VERSION 5.7 ;
  NOWIREEXTENSIONATPIN ON ;
  DIVIDERCHAR "/" ;
  BUSBITCHARS "[]" ;
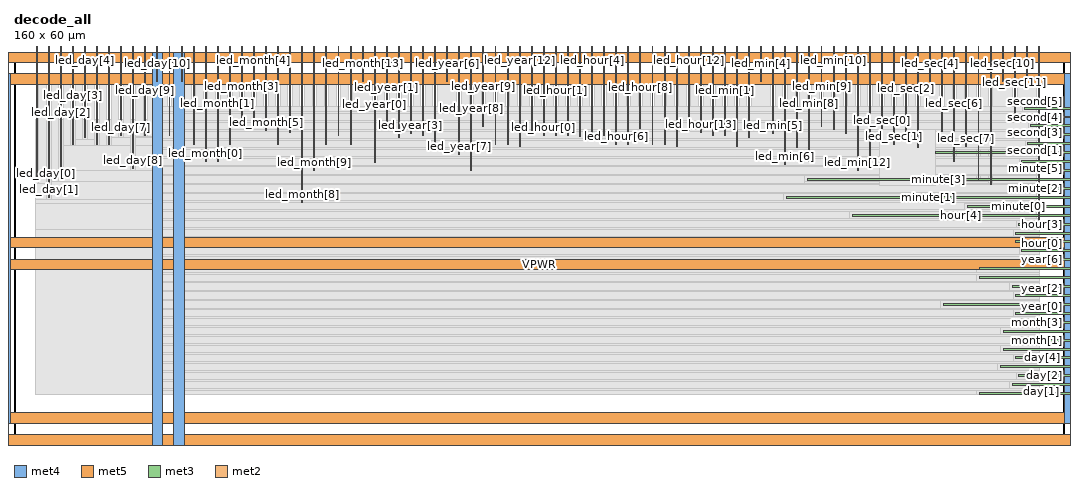
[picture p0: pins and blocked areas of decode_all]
MACRO decode_all
  CLASS BLOCK ;
  FOREIGN decode_all ;
  ORIGIN 0.000 0.000 ;
  SIZE 160.000 BY 60.000 ;
  PIN VGND
    DIRECTION INOUT ;
    USE GROUND ;
    PORT
      LAYER met4 ;
        RECT -5.380 -0.020 -3.780 59.860 ;
    END
    PORT
      LAYER met5 ;
        RECT -5.380 -0.020 165.000 1.580 ;
    END
    PORT
      LAYER met5 ;
        RECT -5.380 58.260 165.000 59.860 ;
    END
    PORT
      LAYER met4 ;
        RECT 163.400 -0.020 165.000 59.860 ;
    END
    PORT
      LAYER met4 ;
        RECT 24.340 -0.020 25.940 59.860 ;
    END
    PORT
      LAYER met5 ;
        RECT -5.380 30.030 165.000 31.630 ;
    END
  END VGND
  PIN VPWR
    DIRECTION INOUT ;
    USE POWER ;
    PORT
      LAYER met4 ;
        RECT -2.080 3.280 -0.480 56.560 ;
    END
    PORT
      LAYER met5 ;
        RECT -2.080 3.280 161.700 4.880 ;
    END
    PORT
      LAYER met5 ;
        RECT -2.080 54.960 161.700 56.560 ;
    END
    PORT
      LAYER met4 ;
        RECT 160.100 3.280 161.700 56.560 ;
    END
    PORT
      LAYER met4 ;
        RECT 21.040 -0.020 22.640 59.860 ;
    END
    PORT
      LAYER met5 ;
        RECT -5.380 26.730 165.000 28.330 ;
    END
  END VPWR
  PIN day[0]
    DIRECTION INPUT ;
    USE SIGNAL ;
    ANTENNAGATEAREA 0.159000 ;
    PORT
      LAYER met3 ;
        RECT 147.110 7.670 161.000 7.970 ;
    END
  END day[0]
  PIN day[1]
    DIRECTION INPUT ;
    USE SIGNAL ;
    ANTENNAGATEAREA 0.213000 ;
    PORT
      LAYER met3 ;
        RECT 152.170 9.030 161.000 9.330 ;
    END
  END day[1]
  PIN day[2]
    DIRECTION INPUT ;
    USE SIGNAL ;
    ANTENNAGATEAREA 0.213000 ;
    PORT
      LAYER met3 ;
        RECT 153.090 10.390 161.000 10.690 ;
    END
  END day[2]
  PIN day[3]
    DIRECTION INPUT ;
    USE SIGNAL ;
    ANTENNAGATEAREA 0.213000 ;
    PORT
      LAYER met3 ;
        RECT 150.330 11.750 161.000 12.050 ;
    END
  END day[3]
  PIN day[4]
    DIRECTION INPUT ;
    USE SIGNAL ;
    ANTENNAGATEAREA 0.159000 ;
    PORT
      LAYER met3 ;
        RECT 152.630 13.110 161.000 13.410 ;
    END
  END day[4]
  PIN hour[0]
    DIRECTION INPUT ;
    USE SIGNAL ;
    ANTENNAGATEAREA 0.213000 ;
    PORT
      LAYER met3 ;
        RECT 153.550 29.430 161.000 29.730 ;
    END
  END hour[0]
  PIN hour[1]
    DIRECTION INPUT ;
    USE SIGNAL ;
    ANTENNAGATEAREA 0.126000 ;
    PORT
      LAYER met3 ;
        RECT 152.630 30.790 161.000 31.090 ;
    END
  END hour[1]
  PIN hour[2]
    DIRECTION INPUT ;
    USE SIGNAL ;
    ANTENNAGATEAREA 0.126000 ;
    PORT
      LAYER met3 ;
        RECT 152.630 32.150 161.000 32.450 ;
    END
  END hour[2]
  PIN hour[3]
    DIRECTION INPUT ;
    USE SIGNAL ;
    ANTENNAGATEAREA 0.196500 ;
    PORT
      LAYER met3 ;
        RECT 153.090 33.510 161.000 33.810 ;
    END
  END hour[3]
  PIN hour[4]
    DIRECTION INPUT ;
    USE SIGNAL ;
    ANTENNAGATEAREA 0.213000 ;
    PORT
      LAYER met3 ;
        RECT 127.790 34.870 161.000 35.170 ;
    END
  END hour[4]
  PIN led_day[0]
    DIRECTION OUTPUT ;
    USE SIGNAL ;
    ANTENNADIFFAREA 0.445500 ;
    PORT
      LAYER met2 ;
        RECT 3.380 40.080 3.520 61.000 ;
    END
  END led_day[0]
  PIN led_day[10]
    DIRECTION OUTPUT ;
    USE SIGNAL ;
    ANTENNADIFFAREA 0.445500 ;
    PORT
      LAYER met2 ;
        RECT 21.780 55.350 21.920 61.000 ;
    END
  END led_day[10]
  PIN led_day[11]
    DIRECTION OUTPUT ;
    USE SIGNAL ;
    ANTENNADIFFAREA 0.445500 ;
    PORT
      LAYER met2 ;
        RECT 23.620 47.190 23.760 61.000 ;
    END
  END led_day[11]
  PIN led_day[12]
    DIRECTION OUTPUT ;
    USE SIGNAL ;
    ANTENNADIFFAREA 0.445500 ;
    PORT
      LAYER met2 ;
        RECT 25.460 55.350 25.600 61.000 ;
    END
  END led_day[12]
  PIN led_day[13]
    DIRECTION OUTPUT ;
    USE SIGNAL ;
    ANTENNADIFFAREA 0.445500 ;
    PORT
      LAYER met2 ;
        RECT 27.300 45.860 27.440 61.000 ;
    END
  END led_day[13]
  PIN led_day[1]
    DIRECTION OUTPUT ;
    USE SIGNAL ;
    ANTENNADIFFAREA 0.445500 ;
    PORT
      LAYER met2 ;
        RECT 5.220 37.700 5.360 61.000 ;
    END
  END led_day[1]
  PIN led_day[2]
    DIRECTION OUTPUT ;
    USE SIGNAL ;
    ANTENNADIFFAREA 0.445500 ;
    PORT
      LAYER met2 ;
        RECT 7.060 40.420 7.200 61.000 ;
    END
  END led_day[2]
  PIN led_day[3]
    DIRECTION OUTPUT ;
    USE SIGNAL ;
    ANTENNADIFFAREA 0.445500 ;
    PORT
      LAYER met2 ;
        RECT 8.900 45.860 9.040 61.000 ;
    END
  END led_day[3]
  PIN led_day[4]
    DIRECTION OUTPUT ;
    USE SIGNAL ;
    ANTENNADIFFAREA 0.445500 ;
    PORT
      LAYER met2 ;
        RECT 10.740 46.880 10.880 61.000 ;
    END
  END led_day[4]
  PIN led_day[5]
    DIRECTION OUTPUT ;
    USE SIGNAL ;
    ANTENNADIFFAREA 0.445500 ;
    PORT
      LAYER met2 ;
        RECT 12.580 45.860 12.720 61.000 ;
    END
  END led_day[5]
  PIN led_day[6]
    DIRECTION OUTPUT ;
    USE SIGNAL ;
    ANTENNADIFFAREA 0.445500 ;
    PORT
      LAYER met2 ;
        RECT 14.420 45.860 14.560 61.000 ;
    END
  END led_day[6]
  PIN led_day[7]
    DIRECTION OUTPUT ;
    USE SIGNAL ;
    ANTENNADIFFAREA 0.445500 ;
    PORT
      LAYER met2 ;
        RECT 16.260 47.190 16.400 61.000 ;
    END
  END led_day[7]
  PIN led_day[8]
    DIRECTION OUTPUT ;
    USE SIGNAL ;
    PORT
      LAYER met2 ;
        RECT 18.100 42.120 18.240 61.000 ;
    END
  END led_day[8]
  PIN led_day[9]
    DIRECTION OUTPUT ;
    USE SIGNAL ;
    ANTENNADIFFAREA 0.445500 ;
    PORT
      LAYER met2 ;
        RECT 19.940 47.220 20.080 61.000 ;
    END
  END led_day[9]
  PIN led_hour[0]
    DIRECTION OUTPUT ;
    USE SIGNAL ;
    ANTENNADIFFAREA 0.445500 ;
    PORT
      LAYER met2 ;
        RECT 80.660 47.220 80.800 61.000 ;
    END
  END led_hour[0]
  PIN led_hour[10]
    DIRECTION OUTPUT ;
    USE SIGNAL ;
    ANTENNADIFFAREA 0.445500 ;
    PORT
      LAYER met2 ;
        RECT 99.060 45.860 99.200 61.000 ;
    END
  END led_hour[10]
  PIN led_hour[11]
    DIRECTION OUTPUT ;
    USE SIGNAL ;
    ANTENNADIFFAREA 0.445500 ;
    PORT
      LAYER met2 ;
        RECT 100.900 45.520 101.040 61.000 ;
    END
  END led_hour[11]
  PIN led_hour[12]
    DIRECTION OUTPUT ;
    USE SIGNAL ;
    ANTENNADIFFAREA 0.445500 ;
    PORT
      LAYER met2 ;
        RECT 102.740 47.870 102.880 61.000 ;
    END
  END led_hour[12]
  PIN led_hour[13]
    DIRECTION OUTPUT ;
    USE SIGNAL ;
    ANTENNADIFFAREA 0.445500 ;
    PORT
      LAYER met2 ;
        RECT 104.580 47.560 104.720 61.000 ;
    END
  END led_hour[13]
  PIN led_hour[1]
    DIRECTION OUTPUT ;
    USE SIGNAL ;
    ANTENNADIFFAREA 0.445500 ;
    PORT
      LAYER met2 ;
        RECT 82.500 47.220 82.640 61.000 ;
    END
  END led_hour[1]
  PIN led_hour[2]
    DIRECTION OUTPUT ;
    USE SIGNAL ;
    ANTENNADIFFAREA 0.445500 ;
    PORT
      LAYER met2 ;
        RECT 84.340 47.220 84.480 61.000 ;
    END
  END led_hour[2]
  PIN led_hour[3]
    DIRECTION OUTPUT ;
    USE SIGNAL ;
    ANTENNADIFFAREA 0.445500 ;
    PORT
      LAYER met2 ;
        RECT 86.180 47.020 86.320 61.000 ;
    END
  END led_hour[3]
  PIN led_hour[4]
    DIRECTION OUTPUT ;
    USE SIGNAL ;
    ANTENNADIFFAREA 0.445500 ;
    PORT
      LAYER met2 ;
        RECT 88.020 47.560 88.160 61.000 ;
    END
  END led_hour[4]
  PIN led_hour[5]
    DIRECTION OUTPUT ;
    USE SIGNAL ;
    ANTENNADIFFAREA 0.445500 ;
    PORT
      LAYER met2 ;
        RECT 89.860 47.220 90.000 61.000 ;
    END
  END led_hour[5]
  PIN led_hour[6]
    DIRECTION OUTPUT ;
    USE SIGNAL ;
    ANTENNADIFFAREA 0.445500 ;
    PORT
      LAYER met2 ;
        RECT 91.700 45.860 91.840 61.000 ;
    END
  END led_hour[6]
  PIN led_hour[7]
    DIRECTION OUTPUT ;
    USE SIGNAL ;
    ANTENNADIFFAREA 0.445500 ;
    PORT
      LAYER met2 ;
        RECT 93.540 45.860 93.680 61.000 ;
    END
  END led_hour[7]
  PIN led_hour[8]
    DIRECTION OUTPUT ;
    USE SIGNAL ;
    PORT
      LAYER met2 ;
        RECT 95.380 48.240 95.520 61.000 ;
    END
  END led_hour[8]
  PIN led_hour[9]
    DIRECTION OUTPUT ;
    USE SIGNAL ;
    ANTENNADIFFAREA 0.445500 ;
    PORT
      LAYER met2 ;
        RECT 97.220 45.860 97.360 61.000 ;
    END
  END led_hour[9]
  PIN led_min[0]
    DIRECTION OUTPUT ;
    USE SIGNAL ;
    ANTENNADIFFAREA 0.445500 ;
    PORT
      LAYER met2 ;
        RECT 106.420 47.190 106.560 61.000 ;
    END
  END led_min[0]
  PIN led_min[10]
    DIRECTION OUTPUT ;
    USE SIGNAL ;
    ANTENNADIFFAREA 0.445500 ;
    PORT
      LAYER met2 ;
        RECT 124.820 48.080 124.960 61.000 ;
    END
  END led_min[10]
  PIN led_min[11]
    DIRECTION OUTPUT ;
    USE SIGNAL ;
    ANTENNADIFFAREA 0.445500 ;
    PORT
      LAYER met2 ;
        RECT 126.660 47.400 126.800 61.000 ;
    END
  END led_min[11]
  PIN led_min[12]
    DIRECTION OUTPUT ;
    USE SIGNAL ;
    ANTENNADIFFAREA 0.445500 ;
    PORT
      LAYER met2 ;
        RECT 128.500 41.780 128.640 61.000 ;
    END
  END led_min[12]
  PIN led_min[13]
    DIRECTION OUTPUT ;
    USE SIGNAL ;
    ANTENNADIFFAREA 0.445500 ;
    PORT
      LAYER met2 ;
        RECT 130.340 44.000 130.480 61.000 ;
    END
  END led_min[13]
  PIN led_min[1]
    DIRECTION OUTPUT ;
    USE SIGNAL ;
    ANTENNADIFFAREA 0.445500 ;
    PORT
      LAYER met2 ;
        RECT 108.260 47.220 108.400 61.000 ;
    END
  END led_min[1]
  PIN led_min[2]
    DIRECTION OUTPUT ;
    USE SIGNAL ;
    ANTENNADIFFAREA 0.445500 ;
    PORT
      LAYER met2 ;
        RECT 110.100 45.520 110.240 61.000 ;
    END
  END led_min[2]
  PIN led_min[3]
    DIRECTION OUTPUT ;
    USE SIGNAL ;
    ANTENNADIFFAREA 0.445500 ;
    PORT
      LAYER met2 ;
        RECT 111.940 46.880 112.080 61.000 ;
    END
  END led_min[3]
  PIN led_min[4]
    DIRECTION OUTPUT ;
    USE SIGNAL ;
    ANTENNADIFFAREA 0.445500 ;
    PORT
      LAYER met2 ;
        RECT 113.780 55.350 113.920 61.000 ;
    END
  END led_min[4]
  PIN led_min[5]
    DIRECTION OUTPUT ;
    USE SIGNAL ;
    ANTENNADIFFAREA 0.445500 ;
    PORT
      LAYER met2 ;
        RECT 115.620 47.400 115.760 61.000 ;
    END
  END led_min[5]
  PIN led_min[6]
    DIRECTION OUTPUT ;
    USE SIGNAL ;
    ANTENNADIFFAREA 0.445500 ;
    PORT
      LAYER met2 ;
        RECT 117.460 42.800 117.600 61.000 ;
    END
  END led_min[6]
  PIN led_min[7]
    DIRECTION OUTPUT ;
    USE SIGNAL ;
    ANTENNADIFFAREA 0.445500 ;
    PORT
      LAYER met2 ;
        RECT 119.300 45.360 119.440 61.000 ;
    END
  END led_min[7]
  PIN led_min[8]
    DIRECTION OUTPUT ;
    USE SIGNAL ;
    ANTENNADIFFAREA 0.445500 ;
    PORT
      LAYER met2 ;
        RECT 121.140 43.140 121.280 61.000 ;
    END
  END led_min[8]
  PIN led_min[9]
    DIRECTION OUTPUT ;
    USE SIGNAL ;
    ANTENNADIFFAREA 0.445500 ;
    PORT
      LAYER met2 ;
        RECT 122.980 48.550 123.120 61.000 ;
    END
  END led_min[9]
  PIN led_month[0]
    DIRECTION OUTPUT ;
    USE SIGNAL ;
    ANTENNADIFFAREA 0.445500 ;
    PORT
      LAYER met2 ;
        RECT 29.140 43.140 29.280 61.000 ;
    END
  END led_month[0]
  PIN led_month[10]
    DIRECTION OUTPUT ;
    USE SIGNAL ;
    ANTENNADIFFAREA 0.445500 ;
    PORT
      LAYER met2 ;
        RECT 47.540 45.860 47.680 61.000 ;
    END
  END led_month[10]
  PIN led_month[11]
    DIRECTION OUTPUT ;
    USE SIGNAL ;
    ANTENNADIFFAREA 0.445500 ;
    PORT
      LAYER met2 ;
        RECT 49.380 47.220 49.520 61.000 ;
    END
  END led_month[11]
  PIN led_month[12]
    DIRECTION OUTPUT ;
    USE SIGNAL ;
    ANTENNADIFFAREA 0.445500 ;
    PORT
      LAYER met2 ;
        RECT 51.220 45.860 51.360 61.000 ;
    END
  END led_month[12]
  PIN led_month[13]
    DIRECTION OUTPUT ;
    USE SIGNAL ;
    PORT
      LAYER met2 ;
        RECT 53.060 55.350 53.200 61.000 ;
    END
  END led_month[13]
  PIN led_month[1]
    DIRECTION OUTPUT ;
    USE SIGNAL ;
    ANTENNADIFFAREA 0.445500 ;
    PORT
      LAYER met2 ;
        RECT 30.980 43.140 31.120 61.000 ;
    END
  END led_month[1]
  PIN led_month[2]
    DIRECTION OUTPUT ;
    USE SIGNAL ;
    ANTENNADIFFAREA 0.445500 ;
    PORT
      LAYER met2 ;
        RECT 32.820 45.860 32.960 61.000 ;
    END
  END led_month[2]
  PIN led_month[3]
    DIRECTION OUTPUT ;
    USE SIGNAL ;
    ANTENNADIFFAREA 0.445500 ;
    PORT
      LAYER met2 ;
        RECT 34.660 48.550 34.800 61.000 ;
    END
  END led_month[3]
  PIN led_month[4]
    DIRECTION OUTPUT ;
    USE SIGNAL ;
    ANTENNADIFFAREA 0.445500 ;
    PORT
      LAYER met2 ;
        RECT 36.500 48.550 36.640 61.000 ;
    END
  END led_month[4]
  PIN led_month[5]
    DIRECTION OUTPUT ;
    USE SIGNAL ;
    ANTENNADIFFAREA 0.445500 ;
    PORT
      LAYER met2 ;
        RECT 38.340 47.870 38.480 61.000 ;
    END
  END led_month[5]
  PIN led_month[6]
    DIRECTION OUTPUT ;
    USE SIGNAL ;
    ANTENNADIFFAREA 0.445500 ;
    PORT
      LAYER met2 ;
        RECT 40.180 45.860 40.320 61.000 ;
    END
  END led_month[6]
  PIN led_month[7]
    DIRECTION OUTPUT ;
    USE SIGNAL ;
    ANTENNADIFFAREA 0.445500 ;
    PORT
      LAYER met2 ;
        RECT 42.020 47.560 42.160 61.000 ;
    END
  END led_month[7]
  PIN led_month[8]
    DIRECTION OUTPUT ;
    USE SIGNAL ;
    PORT
      LAYER met2 ;
        RECT 43.860 37.020 44.000 61.000 ;
    END
  END led_month[8]
  PIN led_month[9]
    DIRECTION OUTPUT ;
    USE SIGNAL ;
    PORT
      LAYER met2 ;
        RECT 45.700 41.780 45.840 61.000 ;
    END
  END led_month[9]
  PIN led_sec[0]
    DIRECTION OUTPUT ;
    USE SIGNAL ;
    ANTENNADIFFAREA 0.445500 ;
    PORT
      LAYER met2 ;
        RECT 132.180 48.230 132.320 61.000 ;
    END
  END led_sec[0]
  PIN led_sec[10]
    DIRECTION OUTPUT ;
    USE SIGNAL ;
    ANTENNADIFFAREA 0.445500 ;
    PORT
      LAYER met2 ;
        RECT 150.580 55.350 150.720 61.000 ;
    END
  END led_sec[10]
  PIN led_sec[11]
    DIRECTION OUTPUT ;
    USE SIGNAL ;
    ANTENNADIFFAREA 0.445500 ;
    PORT
      LAYER met2 ;
        RECT 152.420 49.600 152.560 61.000 ;
    END
  END led_sec[11]
  PIN led_sec[12]
    DIRECTION OUTPUT ;
    USE SIGNAL ;
    ANTENNADIFFAREA 0.445500 ;
    PORT
      LAYER met2 ;
        RECT 154.260 55.350 154.400 61.000 ;
    END
  END led_sec[12]
  PIN led_sec[13]
    DIRECTION OUTPUT ;
    USE SIGNAL ;
    ANTENNADIFFAREA 0.445500 ;
    PORT
      LAYER met2 ;
        RECT 156.100 33.120 156.240 61.000 ;
    END
  END led_sec[13]
  PIN led_sec[1]
    DIRECTION OUTPUT ;
    USE SIGNAL ;
    ANTENNADIFFAREA 0.445500 ;
    PORT
      LAYER met2 ;
        RECT 134.020 45.860 134.160 61.000 ;
    END
  END led_sec[1]
  PIN led_sec[2]
    DIRECTION OUTPUT ;
    USE SIGNAL ;
    ANTENNADIFFAREA 0.445500 ;
    PORT
      LAYER met2 ;
        RECT 135.860 47.700 136.000 61.000 ;
    END
  END led_sec[2]
  PIN led_sec[3]
    DIRECTION OUTPUT ;
    USE SIGNAL ;
    ANTENNADIFFAREA 0.445500 ;
    PORT
      LAYER met2 ;
        RECT 137.700 45.320 137.840 61.000 ;
    END
  END led_sec[3]
  PIN led_sec[4]
    DIRECTION OUTPUT ;
    USE SIGNAL ;
    ANTENNADIFFAREA 0.445500 ;
    PORT
      LAYER met2 ;
        RECT 139.540 55.350 139.680 61.000 ;
    END
  END led_sec[4]
  PIN led_sec[5]
    DIRECTION OUTPUT ;
    USE SIGNAL ;
    ANTENNADIFFAREA 0.445500 ;
    PORT
      LAYER met2 ;
        RECT 141.380 47.700 141.520 61.000 ;
    END
  END led_sec[5]
  PIN led_sec[6]
    DIRECTION OUTPUT ;
    USE SIGNAL ;
    ANTENNADIFFAREA 0.445500 ;
    PORT
      LAYER met2 ;
        RECT 143.220 43.140 143.360 61.000 ;
    END
  END led_sec[6]
  PIN led_sec[7]
    DIRECTION OUTPUT ;
    USE SIGNAL ;
    ANTENNADIFFAREA 0.445500 ;
    PORT
      LAYER met2 ;
        RECT 145.060 45.520 145.200 61.000 ;
    END
  END led_sec[7]
  PIN led_sec[8]
    DIRECTION OUTPUT ;
    USE SIGNAL ;
    ANTENNADIFFAREA 0.445500 ;
    PORT
      LAYER met2 ;
        RECT 146.900 40.420 147.040 61.000 ;
    END
  END led_sec[8]
  PIN led_sec[9]
    DIRECTION OUTPUT ;
    USE SIGNAL ;
    ANTENNADIFFAREA 0.445500 ;
    PORT
      LAYER met2 ;
        RECT 148.740 39.710 148.880 61.000 ;
    END
  END led_sec[9]
  PIN led_year[0]
    DIRECTION OUTPUT ;
    USE SIGNAL ;
    ANTENNADIFFAREA 0.445500 ;
    PORT
      LAYER met2 ;
        RECT 54.900 43.110 55.040 61.000 ;
    END
  END led_year[0]
  PIN led_year[10]
    DIRECTION OUTPUT ;
    USE SIGNAL ;
    ANTENNADIFFAREA 0.445500 ;
    PORT
      LAYER met2 ;
        RECT 73.300 45.860 73.440 61.000 ;
    END
  END led_year[10]
  PIN led_year[11]
    DIRECTION OUTPUT ;
    USE SIGNAL ;
    ANTENNADIFFAREA 0.445500 ;
    PORT
      LAYER met2 ;
        RECT 75.140 45.860 75.280 61.000 ;
    END
  END led_year[11]
  PIN led_year[12]
    DIRECTION OUTPUT ;
    USE SIGNAL ;
    ANTENNADIFFAREA 0.445500 ;
    PORT
      LAYER met2 ;
        RECT 76.980 45.520 77.120 61.000 ;
    END
  END led_year[12]
  PIN led_year[13]
    DIRECTION OUTPUT ;
    USE SIGNAL ;
    ANTENNADIFFAREA 0.445500 ;
    PORT
      LAYER met2 ;
        RECT 78.820 47.220 78.960 61.000 ;
    END
  END led_year[13]
  PIN led_year[1]
    DIRECTION OUTPUT ;
    USE SIGNAL ;
    ANTENNADIFFAREA 0.445500 ;
    PORT
      LAYER met2 ;
        RECT 56.740 48.230 56.880 61.000 ;
    END
  END led_year[1]
  PIN led_year[2]
    DIRECTION OUTPUT ;
    USE SIGNAL ;
    ANTENNADIFFAREA 0.445500 ;
    PORT
      LAYER met2 ;
        RECT 58.580 46.880 58.720 61.000 ;
    END
  END led_year[2]
  PIN led_year[3]
    DIRECTION OUTPUT ;
    USE SIGNAL ;
    ANTENNADIFFAREA 0.445500 ;
    PORT
      LAYER met2 ;
        RECT 60.420 47.400 60.560 61.000 ;
    END
  END led_year[3]
  PIN led_year[4]
    DIRECTION OUTPUT ;
    USE SIGNAL ;
    ANTENNADIFFAREA 0.445500 ;
    PORT
      LAYER met2 ;
        RECT 62.260 47.190 62.400 61.000 ;
    END
  END led_year[4]
  PIN led_year[5]
    DIRECTION OUTPUT ;
    USE SIGNAL ;
    ANTENNADIFFAREA 0.445500 ;
    PORT
      LAYER met2 ;
        RECT 64.100 45.860 64.240 61.000 ;
    END
  END led_year[5]
  PIN led_year[6]
    DIRECTION OUTPUT ;
    USE SIGNAL ;
    ANTENNADIFFAREA 0.445500 ;
    PORT
      LAYER met2 ;
        RECT 65.940 55.350 66.080 61.000 ;
    END
  END led_year[6]
  PIN led_year[7]
    DIRECTION OUTPUT ;
    USE SIGNAL ;
    ANTENNADIFFAREA 0.445500 ;
    PORT
      LAYER met2 ;
        RECT 67.780 44.300 67.920 61.000 ;
    END
  END led_year[7]
  PIN led_year[8]
    DIRECTION OUTPUT ;
    USE SIGNAL ;
    ANTENNADIFFAREA 0.445500 ;
    PORT
      LAYER met2 ;
        RECT 69.620 41.780 69.760 61.000 ;
    END
  END led_year[8]
  PIN led_year[9]
    DIRECTION OUTPUT ;
    USE SIGNAL ;
    ANTENNADIFFAREA 0.445500 ;
    PORT
      LAYER met2 ;
        RECT 71.460 48.550 71.600 61.000 ;
    END
  END led_year[9]
  PIN minute[0]
    DIRECTION INPUT ;
    USE SIGNAL ;
    ANTENNAGATEAREA 0.213000 ;
    PORT
      LAYER met3 ;
        RECT 145.270 36.230 161.000 36.530 ;
    END
  END minute[0]
  PIN minute[1]
    DIRECTION INPUT ;
    USE SIGNAL ;
    ANTENNAGATEAREA 0.196500 ;
    PORT
      LAYER met3 ;
        RECT 117.670 37.590 161.000 37.890 ;
    END
  END minute[1]
  PIN minute[2]
    DIRECTION INPUT ;
    USE SIGNAL ;
    ANTENNAGATEAREA 0.126000 ;
    PORT
      LAYER met3 ;
        RECT 152.630 38.950 161.000 39.250 ;
    END
  END minute[2]
  PIN minute[3]
    DIRECTION INPUT ;
    USE SIGNAL ;
    ANTENNAGATEAREA 0.196500 ;
    PORT
      LAYER met3 ;
        RECT 120.890 40.310 161.000 40.610 ;
    END
  END minute[3]
  PIN minute[4]
    DIRECTION INPUT ;
    USE SIGNAL ;
    ANTENNAGATEAREA 0.159000 ;
    PORT
      LAYER met3 ;
        RECT 153.090 41.670 161.000 41.970 ;
    END
  END minute[4]
  PIN minute[5]
    DIRECTION INPUT ;
    USE SIGNAL ;
    ANTENNAGATEAREA 0.159000 ;
    PORT
      LAYER met3 ;
        RECT 153.550 43.030 161.000 43.330 ;
    END
  END minute[5]
  PIN month[0]
    DIRECTION INPUT ;
    USE SIGNAL ;
    ANTENNAGATEAREA 0.159000 ;
    PORT
      LAYER met3 ;
        RECT 150.790 14.470 161.000 14.770 ;
    END
  END month[0]
  PIN month[1]
    DIRECTION INPUT ;
    USE SIGNAL ;
    ANTENNAGATEAREA 0.159000 ;
    PORT
      LAYER met3 ;
        RECT 152.630 15.830 161.000 16.130 ;
    END
  END month[1]
  PIN month[2]
    DIRECTION INPUT ;
    USE SIGNAL ;
    ANTENNAGATEAREA 0.159000 ;
    PORT
      LAYER met3 ;
        RECT 150.790 17.190 161.000 17.490 ;
    END
  END month[2]
  PIN month[3]
    DIRECTION INPUT ;
    USE SIGNAL ;
    ANTENNAGATEAREA 0.213000 ;
    PORT
      LAYER met3 ;
        RECT 153.090 18.550 161.000 18.850 ;
    END
  END month[3]
  PIN second[0]
    DIRECTION INPUT ;
    USE SIGNAL ;
    ANTENNAGATEAREA 0.213000 ;
    PORT
      LAYER met3 ;
        RECT 140.460 44.390 161.000 44.690 ;
    END
  END second[0]
  PIN second[1]
    DIRECTION INPUT ;
    USE SIGNAL ;
    ANTENNAGATEAREA 0.196500 ;
    PORT
      LAYER met3 ;
        RECT 154.470 45.750 161.000 46.050 ;
    END
  END second[1]
  PIN second[2]
    DIRECTION INPUT ;
    USE SIGNAL ;
    ANTENNAGATEAREA 0.126000 ;
    PORT
      LAYER met3 ;
        RECT 152.630 47.110 161.000 47.410 ;
    END
  END second[2]
  PIN second[3]
    DIRECTION INPUT ;
    USE SIGNAL ;
    ANTENNAGATEAREA 0.196500 ;
    PORT
      LAYER met3 ;
        RECT 154.930 48.470 161.000 48.770 ;
    END
  END second[3]
  PIN second[4]
    DIRECTION INPUT ;
    USE SIGNAL ;
    ANTENNAGATEAREA 0.159000 ;
    PORT
      LAYER met3 ;
        RECT 155.390 49.830 161.000 50.130 ;
    END
  END second[4]
  PIN second[5]
    DIRECTION INPUT ;
    USE SIGNAL ;
    ANTENNAGATEAREA 0.213000 ;
    PORT
      LAYER met3 ;
        RECT 154.010 51.190 161.000 51.490 ;
    END
  END second[5]
  PIN year[0]
    DIRECTION INPUT ;
    USE SIGNAL ;
    ANTENNAGATEAREA 0.159000 ;
    PORT
      LAYER met3 ;
        RECT 152.630 19.910 161.000 20.210 ;
    END
  END year[0]
  PIN year[1]
    DIRECTION INPUT ;
    USE SIGNAL ;
    ANTENNAGATEAREA 0.196500 ;
    PORT
      LAYER met3 ;
        RECT 141.590 21.270 161.000 21.570 ;
    END
  END year[1]
  PIN year[2]
    DIRECTION INPUT ;
    USE SIGNAL ;
    ANTENNAGATEAREA 0.126000 ;
    PORT
      LAYER met3 ;
        RECT 152.630 22.630 161.000 22.930 ;
    END
  END year[2]
  PIN year[3]
    DIRECTION INPUT ;
    USE SIGNAL ;
    ANTENNAGATEAREA 0.213000 ;
    PORT
      LAYER met3 ;
        RECT 152.170 23.990 161.000 24.290 ;
    END
  END year[3]
  PIN year[4]
    DIRECTION INPUT ;
    USE SIGNAL ;
    ANTENNAGATEAREA 0.159000 ;
    PORT
      LAYER met3 ;
        RECT 147.110 25.350 161.000 25.650 ;
    END
  END year[4]
  PIN year[5]
    DIRECTION INPUT ;
    USE SIGNAL ;
    ANTENNAGATEAREA 0.247500 ;
    PORT
      LAYER met3 ;
        RECT 147.110 26.710 161.000 27.010 ;
    END
  END year[5]
  PIN year[6]
    DIRECTION INPUT ;
    USE SIGNAL ;
    ANTENNAGATEAREA 0.159000 ;
    PORT
      LAYER met3 ;
        RECT 154.010 28.070 161.000 28.370 ;
    END
  END year[6]
  OBS
      LAYER nwell ;
        RECT 5.330 10.795 154.290 49.045 ;
      LAYER li1 ;
        RECT 5.520 10.795 154.100 49.045 ;
      LAYER met1 ;
        RECT 3.290 10.640 155.870 49.600 ;
      LAYER met2 ;
        RECT 3.800 39.800 4.940 56.170 ;
        RECT 3.320 37.420 4.940 39.800 ;
        RECT 5.640 40.140 6.780 56.170 ;
        RECT 7.480 45.580 8.620 56.170 ;
        RECT 9.320 46.600 10.460 56.170 ;
        RECT 11.160 46.600 12.300 56.170 ;
        RECT 9.320 45.580 12.300 46.600 ;
        RECT 13.000 45.580 14.140 56.170 ;
        RECT 14.840 46.910 15.980 56.170 ;
        RECT 16.680 46.910 17.820 56.170 ;
        RECT 14.840 45.580 17.820 46.910 ;
        RECT 7.480 41.840 17.820 45.580 ;
        RECT 18.520 46.940 19.660 56.170 ;
        RECT 20.360 55.070 21.500 56.170 ;
        RECT 22.200 55.070 23.340 56.170 ;
        RECT 20.360 46.940 23.340 55.070 ;
        RECT 18.520 46.910 23.340 46.940 ;
        RECT 24.040 55.070 25.180 56.170 ;
        RECT 25.880 55.070 27.020 56.170 ;
        RECT 24.040 46.910 27.020 55.070 ;
        RECT 18.520 45.580 27.020 46.910 ;
        RECT 27.720 45.580 28.860 56.170 ;
        RECT 18.520 42.860 28.860 45.580 ;
        RECT 29.560 42.860 30.700 56.170 ;
        RECT 31.400 45.580 32.540 56.170 ;
        RECT 33.240 48.270 34.380 56.170 ;
        RECT 35.080 48.270 36.220 56.170 ;
        RECT 36.920 48.270 38.060 56.170 ;
        RECT 33.240 47.590 38.060 48.270 ;
        RECT 38.760 47.590 39.900 56.170 ;
        RECT 33.240 45.580 39.900 47.590 ;
        RECT 40.600 47.280 41.740 56.170 ;
        RECT 42.440 47.280 43.580 56.170 ;
        RECT 40.600 45.580 43.580 47.280 ;
        RECT 31.400 42.860 43.580 45.580 ;
        RECT 18.520 41.840 43.580 42.860 ;
        RECT 7.480 40.140 43.580 41.840 ;
        RECT 5.640 37.420 43.580 40.140 ;
        RECT 3.320 36.740 43.580 37.420 ;
        RECT 44.280 41.500 45.420 56.170 ;
        RECT 46.120 45.580 47.260 56.170 ;
        RECT 47.960 46.940 49.100 56.170 ;
        RECT 49.800 46.940 50.940 56.170 ;
        RECT 47.960 45.580 50.940 46.940 ;
        RECT 51.640 55.070 52.780 56.170 ;
        RECT 53.480 55.070 54.620 56.170 ;
        RECT 51.640 45.580 54.620 55.070 ;
        RECT 46.120 42.830 54.620 45.580 ;
        RECT 55.320 47.950 56.460 56.170 ;
        RECT 57.160 47.950 58.300 56.170 ;
        RECT 55.320 46.600 58.300 47.950 ;
        RECT 59.000 47.120 60.140 56.170 ;
        RECT 60.840 47.120 61.980 56.170 ;
        RECT 59.000 46.910 61.980 47.120 ;
        RECT 62.680 46.910 63.820 56.170 ;
        RECT 59.000 46.600 63.820 46.910 ;
        RECT 55.320 45.580 63.820 46.600 ;
        RECT 64.520 55.070 65.660 56.170 ;
        RECT 66.360 55.070 67.500 56.170 ;
        RECT 64.520 45.580 67.500 55.070 ;
        RECT 55.320 44.020 67.500 45.580 ;
        RECT 68.200 44.020 69.340 56.170 ;
        RECT 55.320 42.830 69.340 44.020 ;
        RECT 46.120 41.500 69.340 42.830 ;
        RECT 70.040 48.270 71.180 56.170 ;
        RECT 71.880 48.270 73.020 56.170 ;
        RECT 70.040 45.580 73.020 48.270 ;
        RECT 73.720 45.580 74.860 56.170 ;
        RECT 75.560 45.580 76.700 56.170 ;
        RECT 70.040 45.240 76.700 45.580 ;
        RECT 77.400 46.940 78.540 56.170 ;
        RECT 79.240 46.940 80.380 56.170 ;
        RECT 81.080 46.940 82.220 56.170 ;
        RECT 82.920 46.940 84.060 56.170 ;
        RECT 84.760 46.940 85.900 56.170 ;
        RECT 77.400 46.740 85.900 46.940 ;
        RECT 86.600 47.280 87.740 56.170 ;
        RECT 88.440 47.280 89.580 56.170 ;
        RECT 86.600 46.940 89.580 47.280 ;
        RECT 90.280 46.940 91.420 56.170 ;
        RECT 86.600 46.740 91.420 46.940 ;
        RECT 77.400 45.580 91.420 46.740 ;
        RECT 92.120 45.580 93.260 56.170 ;
        RECT 93.960 47.960 95.100 56.170 ;
        RECT 95.800 47.960 96.940 56.170 ;
        RECT 93.960 45.580 96.940 47.960 ;
        RECT 97.640 45.580 98.780 56.170 ;
        RECT 99.480 45.580 100.620 56.170 ;
        RECT 77.400 45.240 100.620 45.580 ;
        RECT 101.320 47.590 102.460 56.170 ;
        RECT 103.160 47.590 104.300 56.170 ;
        RECT 101.320 47.280 104.300 47.590 ;
        RECT 105.000 47.280 106.140 56.170 ;
        RECT 101.320 46.910 106.140 47.280 ;
        RECT 106.840 46.940 107.980 56.170 ;
        RECT 108.680 46.940 109.820 56.170 ;
        RECT 106.840 46.910 109.820 46.940 ;
        RECT 101.320 45.240 109.820 46.910 ;
        RECT 110.520 46.600 111.660 56.170 ;
        RECT 112.360 55.070 113.500 56.170 ;
        RECT 114.200 55.070 115.340 56.170 ;
        RECT 112.360 47.120 115.340 55.070 ;
        RECT 116.040 47.120 117.180 56.170 ;
        RECT 112.360 46.600 117.180 47.120 ;
        RECT 110.520 45.240 117.180 46.600 ;
        RECT 70.040 42.520 117.180 45.240 ;
        RECT 117.880 45.080 119.020 56.170 ;
        RECT 119.720 45.080 120.860 56.170 ;
        RECT 117.880 42.860 120.860 45.080 ;
        RECT 121.560 48.270 122.700 56.170 ;
        RECT 123.400 48.270 124.540 56.170 ;
        RECT 121.560 47.800 124.540 48.270 ;
        RECT 125.240 47.800 126.380 56.170 ;
        RECT 121.560 47.120 126.380 47.800 ;
        RECT 127.080 47.120 128.220 56.170 ;
        RECT 121.560 42.860 128.220 47.120 ;
        RECT 117.880 42.520 128.220 42.860 ;
        RECT 70.040 41.500 128.220 42.520 ;
        RECT 128.920 43.720 130.060 56.170 ;
        RECT 130.760 47.950 131.900 56.170 ;
        RECT 132.600 47.950 133.740 56.170 ;
        RECT 130.760 45.580 133.740 47.950 ;
        RECT 134.440 47.420 135.580 56.170 ;
        RECT 136.280 47.420 137.420 56.170 ;
        RECT 134.440 45.580 137.420 47.420 ;
        RECT 130.760 45.040 137.420 45.580 ;
        RECT 138.120 55.070 139.260 56.170 ;
        RECT 139.960 55.070 141.100 56.170 ;
        RECT 138.120 47.420 141.100 55.070 ;
        RECT 141.800 47.420 142.940 56.170 ;
        RECT 138.120 45.040 142.940 47.420 ;
        RECT 130.760 43.720 142.940 45.040 ;
        RECT 128.920 42.860 142.940 43.720 ;
        RECT 143.640 45.240 144.780 56.170 ;
        RECT 145.480 45.240 146.620 56.170 ;
        RECT 143.640 42.860 146.620 45.240 ;
        RECT 128.920 41.500 146.620 42.860 ;
        RECT 44.280 40.140 146.620 41.500 ;
        RECT 147.320 40.140 148.460 56.170 ;
        RECT 44.280 39.430 148.460 40.140 ;
        RECT 149.160 55.070 150.300 56.170 ;
        RECT 151.000 55.070 152.140 56.170 ;
        RECT 149.160 49.320 152.140 55.070 ;
        RECT 152.840 55.070 153.980 56.170 ;
        RECT 154.680 55.070 155.820 56.170 ;
        RECT 152.840 49.320 155.820 55.070 ;
        RECT 149.160 39.430 155.820 49.320 ;
        RECT 44.280 36.740 155.820 39.430 ;
        RECT 3.320 32.840 155.820 36.740 ;
        RECT 3.320 7.635 156.310 32.840 ;
      LAYER met3 ;
        RECT 21.050 50.790 153.610 51.505 ;
        RECT 21.050 50.530 156.335 50.790 ;
        RECT 21.050 49.430 154.990 50.530 ;
        RECT 21.050 49.170 156.335 49.430 ;
        RECT 21.050 48.070 154.530 49.170 ;
        RECT 21.050 47.810 156.335 48.070 ;
        RECT 21.050 46.710 152.230 47.810 ;
        RECT 21.050 46.450 156.335 46.710 ;
        RECT 21.050 45.350 154.070 46.450 ;
        RECT 21.050 45.090 156.335 45.350 ;
        RECT 21.050 43.990 140.060 45.090 ;
        RECT 21.050 43.730 156.335 43.990 ;
        RECT 21.050 42.630 153.150 43.730 ;
        RECT 21.050 42.370 156.335 42.630 ;
        RECT 21.050 41.270 152.690 42.370 ;
        RECT 21.050 41.010 156.335 41.270 ;
        RECT 21.050 39.910 120.490 41.010 ;
        RECT 21.050 39.650 156.335 39.910 ;
        RECT 21.050 38.550 152.230 39.650 ;
        RECT 21.050 38.290 156.335 38.550 ;
        RECT 21.050 37.190 117.270 38.290 ;
        RECT 21.050 36.930 156.335 37.190 ;
        RECT 21.050 35.830 144.870 36.930 ;
        RECT 21.050 35.570 156.335 35.830 ;
        RECT 21.050 34.470 127.390 35.570 ;
        RECT 21.050 34.210 156.335 34.470 ;
        RECT 21.050 33.110 152.690 34.210 ;
        RECT 21.050 32.850 156.335 33.110 ;
        RECT 21.050 31.750 152.230 32.850 ;
        RECT 21.050 31.490 156.335 31.750 ;
        RECT 21.050 30.390 152.230 31.490 ;
        RECT 21.050 30.130 156.335 30.390 ;
        RECT 21.050 29.030 153.150 30.130 ;
        RECT 21.050 28.770 156.335 29.030 ;
        RECT 21.050 27.670 153.610 28.770 ;
        RECT 21.050 27.410 156.335 27.670 ;
        RECT 21.050 26.310 146.710 27.410 ;
        RECT 21.050 26.050 156.335 26.310 ;
        RECT 21.050 24.950 146.710 26.050 ;
        RECT 21.050 24.690 156.335 24.950 ;
        RECT 21.050 23.590 151.770 24.690 ;
        RECT 21.050 23.330 156.335 23.590 ;
        RECT 21.050 22.230 152.230 23.330 ;
        RECT 21.050 21.970 156.335 22.230 ;
        RECT 21.050 20.870 141.190 21.970 ;
        RECT 21.050 20.610 156.335 20.870 ;
        RECT 21.050 19.510 152.230 20.610 ;
        RECT 21.050 19.250 156.335 19.510 ;
        RECT 21.050 18.150 152.690 19.250 ;
        RECT 21.050 17.890 156.335 18.150 ;
        RECT 21.050 16.790 150.390 17.890 ;
        RECT 21.050 16.530 156.335 16.790 ;
        RECT 21.050 15.430 152.230 16.530 ;
        RECT 21.050 15.170 156.335 15.430 ;
        RECT 21.050 14.070 150.390 15.170 ;
        RECT 21.050 13.810 156.335 14.070 ;
        RECT 21.050 12.710 152.230 13.810 ;
        RECT 21.050 12.450 156.335 12.710 ;
        RECT 21.050 11.350 149.930 12.450 ;
        RECT 21.050 11.090 156.335 11.350 ;
        RECT 21.050 9.990 152.690 11.090 ;
        RECT 21.050 9.730 156.335 9.990 ;
        RECT 21.050 8.630 151.770 9.730 ;
        RECT 21.050 8.370 156.335 8.630 ;
        RECT 21.050 7.655 146.710 8.370 ;
      LAYER met4 ;
        RECT 131.855 39.615 140.465 48.105 ;
  END
END decode_all
END LIBRARY

